VERSION 5.7 ;
BUSBITCHARS "[]" ;
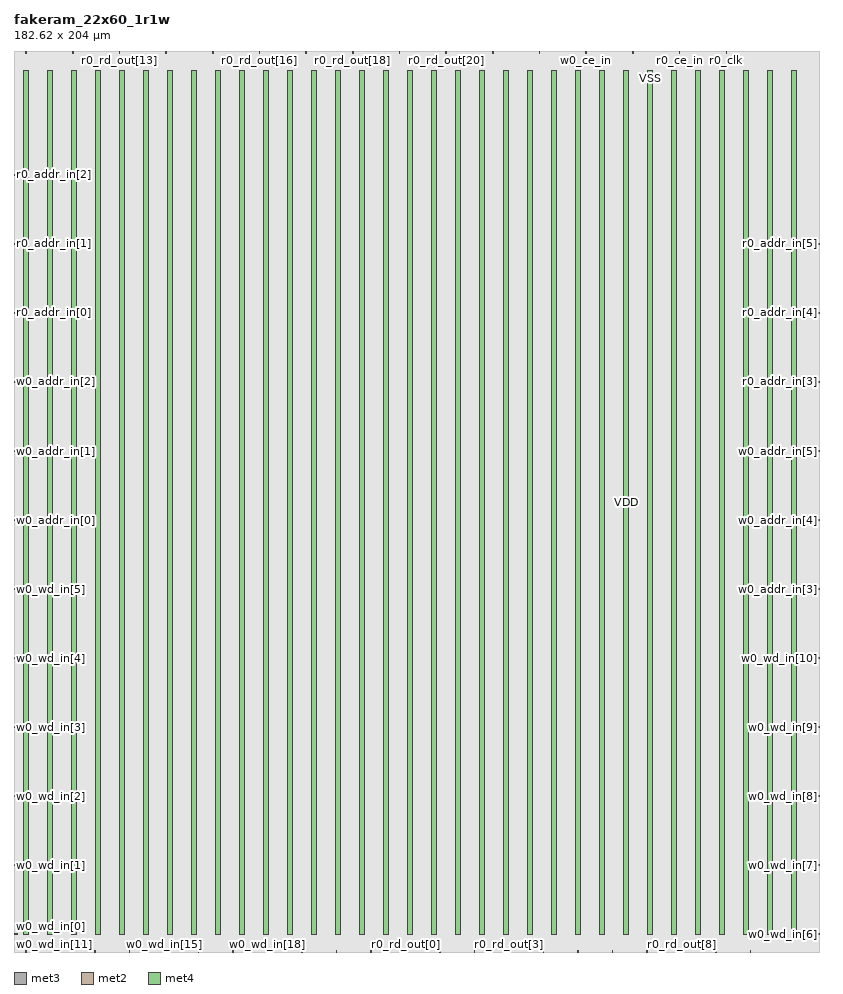
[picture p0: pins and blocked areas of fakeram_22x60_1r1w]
MACRO fakeram_22x60_1r1w
  FOREIGN fakeram_22x60_1r1w 0 0 ;
  SYMMETRY X Y R90 ;
  SIZE 182.620 BY 204.000 ;
  CLASS BLOCK ;
  PIN w0_wd_in[0]
    DIRECTION INPUT ;
    USE SIGNAL ;
    SHAPE ABUTMENT ;
    PORT
      LAYER met3 ;
      RECT 0.000 3.930 0.900 4.230 ;
    END
  END w0_wd_in[0]
  PIN w0_wd_in[1]
    DIRECTION INPUT ;
    USE SIGNAL ;
    SHAPE ABUTMENT ;
    PORT
      LAYER met3 ;
      RECT 0.000 19.570 0.900 19.870 ;
    END
  END w0_wd_in[1]
  PIN w0_wd_in[2]
    DIRECTION INPUT ;
    USE SIGNAL ;
    SHAPE ABUTMENT ;
    PORT
      LAYER met3 ;
      RECT 0.000 35.210 0.900 35.510 ;
    END
  END w0_wd_in[2]
  PIN w0_wd_in[3]
    DIRECTION INPUT ;
    USE SIGNAL ;
    SHAPE ABUTMENT ;
    PORT
      LAYER met3 ;
      RECT 0.000 50.850 0.900 51.150 ;
    END
  END w0_wd_in[3]
  PIN w0_wd_in[4]
    DIRECTION INPUT ;
    USE SIGNAL ;
    SHAPE ABUTMENT ;
    PORT
      LAYER met3 ;
      RECT 0.000 66.490 0.900 66.790 ;
    END
  END w0_wd_in[4]
  PIN w0_wd_in[5]
    DIRECTION INPUT ;
    USE SIGNAL ;
    SHAPE ABUTMENT ;
    PORT
      LAYER met3 ;
      RECT 0.000 82.130 0.900 82.430 ;
    END
  END w0_wd_in[5]
  PIN w0_wd_in[6]
    DIRECTION INPUT ;
    USE SIGNAL ;
    SHAPE ABUTMENT ;
    PORT
      LAYER met3 ;
      RECT 181.720 3.930 182.620 4.230 ;
    END
  END w0_wd_in[6]
  PIN w0_wd_in[7]
    DIRECTION INPUT ;
    USE SIGNAL ;
    SHAPE ABUTMENT ;
    PORT
      LAYER met3 ;
      RECT 181.720 19.570 182.620 19.870 ;
    END
  END w0_wd_in[7]
  PIN w0_wd_in[8]
    DIRECTION INPUT ;
    USE SIGNAL ;
    SHAPE ABUTMENT ;
    PORT
      LAYER met3 ;
      RECT 181.720 35.210 182.620 35.510 ;
    END
  END w0_wd_in[8]
  PIN w0_wd_in[9]
    DIRECTION INPUT ;
    USE SIGNAL ;
    SHAPE ABUTMENT ;
    PORT
      LAYER met3 ;
      RECT 181.720 50.850 182.620 51.150 ;
    END
  END w0_wd_in[9]
  PIN w0_wd_in[10]
    DIRECTION INPUT ;
    USE SIGNAL ;
    SHAPE ABUTMENT ;
    PORT
      LAYER met3 ;
      RECT 181.720 66.490 182.620 66.790 ;
    END
  END w0_wd_in[10]
  PIN w0_wd_in[11]
    DIRECTION INPUT ;
    USE SIGNAL ;
    SHAPE ABUTMENT ;
    PORT
      LAYER met2 ;
      RECT 2.690 0.000 2.830 0.420 ;
    END
  END w0_wd_in[11]
  PIN w0_wd_in[12]
    DIRECTION INPUT ;
    USE SIGNAL ;
    SHAPE ABUTMENT ;
    PORT
      LAYER met2 ;
      RECT 10.510 0.000 10.650 0.420 ;
    END
  END w0_wd_in[12]
  PIN w0_wd_in[13]
    DIRECTION INPUT ;
    USE SIGNAL ;
    SHAPE ABUTMENT ;
    PORT
      LAYER met2 ;
      RECT 18.330 0.000 18.470 0.420 ;
    END
  END w0_wd_in[13]
  PIN w0_wd_in[14]
    DIRECTION INPUT ;
    USE SIGNAL ;
    SHAPE ABUTMENT ;
    PORT
      LAYER met2 ;
      RECT 26.150 0.000 26.290 0.420 ;
    END
  END w0_wd_in[14]
  PIN w0_wd_in[15]
    DIRECTION INPUT ;
    USE SIGNAL ;
    SHAPE ABUTMENT ;
    PORT
      LAYER met2 ;
      RECT 33.970 0.000 34.110 0.420 ;
    END
  END w0_wd_in[15]
  PIN w0_wd_in[16]
    DIRECTION INPUT ;
    USE SIGNAL ;
    SHAPE ABUTMENT ;
    PORT
      LAYER met2 ;
      RECT 41.790 0.000 41.930 0.420 ;
    END
  END w0_wd_in[16]
  PIN w0_wd_in[17]
    DIRECTION INPUT ;
    USE SIGNAL ;
    SHAPE ABUTMENT ;
    PORT
      LAYER met2 ;
      RECT 49.610 0.000 49.750 0.420 ;
    END
  END w0_wd_in[17]
  PIN w0_wd_in[18]
    DIRECTION INPUT ;
    USE SIGNAL ;
    SHAPE ABUTMENT ;
    PORT
      LAYER met2 ;
      RECT 57.430 0.000 57.570 0.420 ;
    END
  END w0_wd_in[18]
  PIN w0_wd_in[19]
    DIRECTION INPUT ;
    USE SIGNAL ;
    SHAPE ABUTMENT ;
    PORT
      LAYER met2 ;
      RECT 65.250 0.000 65.390 0.420 ;
    END
  END w0_wd_in[19]
  PIN w0_wd_in[20]
    DIRECTION INPUT ;
    USE SIGNAL ;
    SHAPE ABUTMENT ;
    PORT
      LAYER met2 ;
      RECT 73.070 0.000 73.210 0.420 ;
    END
  END w0_wd_in[20]
  PIN w0_wd_in[21]
    DIRECTION INPUT ;
    USE SIGNAL ;
    SHAPE ABUTMENT ;
    PORT
      LAYER met2 ;
      RECT 80.890 0.000 81.030 0.420 ;
    END
  END w0_wd_in[21]
  PIN r0_rd_out[0]
    DIRECTION OUTPUT ;
    USE SIGNAL ;
    SHAPE ABUTMENT ;
    PORT
      LAYER met2 ;
      RECT 88.710 0.000 88.850 0.420 ;
    END
  END r0_rd_out[0]
  PIN r0_rd_out[1]
    DIRECTION OUTPUT ;
    USE SIGNAL ;
    SHAPE ABUTMENT ;
    PORT
      LAYER met2 ;
      RECT 96.530 0.000 96.670 0.420 ;
    END
  END r0_rd_out[1]
  PIN r0_rd_out[2]
    DIRECTION OUTPUT ;
    USE SIGNAL ;
    SHAPE ABUTMENT ;
    PORT
      LAYER met2 ;
      RECT 104.350 0.000 104.490 0.420 ;
    END
  END r0_rd_out[2]
  PIN r0_rd_out[3]
    DIRECTION OUTPUT ;
    USE SIGNAL ;
    SHAPE ABUTMENT ;
    PORT
      LAYER met2 ;
      RECT 112.170 0.000 112.310 0.420 ;
    END
  END r0_rd_out[3]
  PIN r0_rd_out[4]
    DIRECTION OUTPUT ;
    USE SIGNAL ;
    SHAPE ABUTMENT ;
    PORT
      LAYER met2 ;
      RECT 119.990 0.000 120.130 0.420 ;
    END
  END r0_rd_out[4]
  PIN r0_rd_out[5]
    DIRECTION OUTPUT ;
    USE SIGNAL ;
    SHAPE ABUTMENT ;
    PORT
      LAYER met2 ;
      RECT 127.810 0.000 127.950 0.420 ;
    END
  END r0_rd_out[5]
  PIN r0_rd_out[6]
    DIRECTION OUTPUT ;
    USE SIGNAL ;
    SHAPE ABUTMENT ;
    PORT
      LAYER met2 ;
      RECT 135.630 0.000 135.770 0.420 ;
    END
  END r0_rd_out[6]
  PIN r0_rd_out[7]
    DIRECTION OUTPUT ;
    USE SIGNAL ;
    SHAPE ABUTMENT ;
    PORT
      LAYER met2 ;
      RECT 143.450 0.000 143.590 0.420 ;
    END
  END r0_rd_out[7]
  PIN r0_rd_out[8]
    DIRECTION OUTPUT ;
    USE SIGNAL ;
    SHAPE ABUTMENT ;
    PORT
      LAYER met2 ;
      RECT 151.270 0.000 151.410 0.420 ;
    END
  END r0_rd_out[8]
  PIN r0_rd_out[9]
    DIRECTION OUTPUT ;
    USE SIGNAL ;
    SHAPE ABUTMENT ;
    PORT
      LAYER met2 ;
      RECT 159.090 0.000 159.230 0.420 ;
    END
  END r0_rd_out[9]
  PIN r0_rd_out[10]
    DIRECTION OUTPUT ;
    USE SIGNAL ;
    SHAPE ABUTMENT ;
    PORT
      LAYER met2 ;
      RECT 166.910 0.000 167.050 0.420 ;
    END
  END r0_rd_out[10]
  PIN r0_rd_out[11]
    DIRECTION OUTPUT ;
    USE SIGNAL ;
    SHAPE ABUTMENT ;
    PORT
      LAYER met2 ;
      RECT 2.690 203.580 2.830 204.000 ;
    END
  END r0_rd_out[11]
  PIN r0_rd_out[12]
    DIRECTION OUTPUT ;
    USE SIGNAL ;
    SHAPE ABUTMENT ;
    PORT
      LAYER met2 ;
      RECT 13.270 203.580 13.410 204.000 ;
    END
  END r0_rd_out[12]
  PIN r0_rd_out[13]
    DIRECTION OUTPUT ;
    USE SIGNAL ;
    SHAPE ABUTMENT ;
    PORT
      LAYER met2 ;
      RECT 23.850 203.580 23.990 204.000 ;
    END
  END r0_rd_out[13]
  PIN r0_rd_out[14]
    DIRECTION OUTPUT ;
    USE SIGNAL ;
    SHAPE ABUTMENT ;
    PORT
      LAYER met2 ;
      RECT 34.430 203.580 34.570 204.000 ;
    END
  END r0_rd_out[14]
  PIN r0_rd_out[15]
    DIRECTION OUTPUT ;
    USE SIGNAL ;
    SHAPE ABUTMENT ;
    PORT
      LAYER met2 ;
      RECT 45.010 203.580 45.150 204.000 ;
    END
  END r0_rd_out[15]
  PIN r0_rd_out[16]
    DIRECTION OUTPUT ;
    USE SIGNAL ;
    SHAPE ABUTMENT ;
    PORT
      LAYER met2 ;
      RECT 55.590 203.580 55.730 204.000 ;
    END
  END r0_rd_out[16]
  PIN r0_rd_out[17]
    DIRECTION OUTPUT ;
    USE SIGNAL ;
    SHAPE ABUTMENT ;
    PORT
      LAYER met2 ;
      RECT 66.170 203.580 66.310 204.000 ;
    END
  END r0_rd_out[17]
  PIN r0_rd_out[18]
    DIRECTION OUTPUT ;
    USE SIGNAL ;
    SHAPE ABUTMENT ;
    PORT
      LAYER met2 ;
      RECT 76.750 203.580 76.890 204.000 ;
    END
  END r0_rd_out[18]
  PIN r0_rd_out[19]
    DIRECTION OUTPUT ;
    USE SIGNAL ;
    SHAPE ABUTMENT ;
    PORT
      LAYER met2 ;
      RECT 87.330 203.580 87.470 204.000 ;
    END
  END r0_rd_out[19]
  PIN r0_rd_out[20]
    DIRECTION OUTPUT ;
    USE SIGNAL ;
    SHAPE ABUTMENT ;
    PORT
      LAYER met2 ;
      RECT 97.910 203.580 98.050 204.000 ;
    END
  END r0_rd_out[20]
  PIN r0_rd_out[21]
    DIRECTION OUTPUT ;
    USE SIGNAL ;
    SHAPE ABUTMENT ;
    PORT
      LAYER met2 ;
      RECT 108.490 203.580 108.630 204.000 ;
    END
  END r0_rd_out[21]
  PIN w0_addr_in[0]
    DIRECTION INPUT ;
    USE SIGNAL ;
    SHAPE ABUTMENT ;
    PORT
      LAYER met3 ;
      RECT 0.000 97.770 0.900 98.070 ;
    END
  END w0_addr_in[0]
  PIN w0_addr_in[1]
    DIRECTION INPUT ;
    USE SIGNAL ;
    SHAPE ABUTMENT ;
    PORT
      LAYER met3 ;
      RECT 0.000 113.410 0.900 113.710 ;
    END
  END w0_addr_in[1]
  PIN w0_addr_in[2]
    DIRECTION INPUT ;
    USE SIGNAL ;
    SHAPE ABUTMENT ;
    PORT
      LAYER met3 ;
      RECT 0.000 129.050 0.900 129.350 ;
    END
  END w0_addr_in[2]
  PIN w0_addr_in[3]
    DIRECTION INPUT ;
    USE SIGNAL ;
    SHAPE ABUTMENT ;
    PORT
      LAYER met3 ;
      RECT 181.720 82.130 182.620 82.430 ;
    END
  END w0_addr_in[3]
  PIN w0_addr_in[4]
    DIRECTION INPUT ;
    USE SIGNAL ;
    SHAPE ABUTMENT ;
    PORT
      LAYER met3 ;
      RECT 181.720 97.770 182.620 98.070 ;
    END
  END w0_addr_in[4]
  PIN w0_addr_in[5]
    DIRECTION INPUT ;
    USE SIGNAL ;
    SHAPE ABUTMENT ;
    PORT
      LAYER met3 ;
      RECT 181.720 113.410 182.620 113.710 ;
    END
  END w0_addr_in[5]
  PIN r0_addr_in[0]
    DIRECTION INPUT ;
    USE SIGNAL ;
    SHAPE ABUTMENT ;
    PORT
      LAYER met3 ;
      RECT 0.000 144.690 0.900 144.990 ;
    END
  END r0_addr_in[0]
  PIN r0_addr_in[1]
    DIRECTION INPUT ;
    USE SIGNAL ;
    SHAPE ABUTMENT ;
    PORT
      LAYER met3 ;
      RECT 0.000 160.330 0.900 160.630 ;
    END
  END r0_addr_in[1]
  PIN r0_addr_in[2]
    DIRECTION INPUT ;
    USE SIGNAL ;
    SHAPE ABUTMENT ;
    PORT
      LAYER met3 ;
      RECT 0.000 175.970 0.900 176.270 ;
    END
  END r0_addr_in[2]
  PIN r0_addr_in[3]
    DIRECTION INPUT ;
    USE SIGNAL ;
    SHAPE ABUTMENT ;
    PORT
      LAYER met3 ;
      RECT 181.720 129.050 182.620 129.350 ;
    END
  END r0_addr_in[3]
  PIN r0_addr_in[4]
    DIRECTION INPUT ;
    USE SIGNAL ;
    SHAPE ABUTMENT ;
    PORT
      LAYER met3 ;
      RECT 181.720 144.690 182.620 144.990 ;
    END
  END r0_addr_in[4]
  PIN r0_addr_in[5]
    DIRECTION INPUT ;
    USE SIGNAL ;
    SHAPE ABUTMENT ;
    PORT
      LAYER met3 ;
      RECT 181.720 160.330 182.620 160.630 ;
    END
  END r0_addr_in[5]
  PIN w0_we_in
    DIRECTION INPUT ;
    USE SIGNAL ;
    SHAPE ABUTMENT ;
    PORT
      LAYER met2 ;
      RECT 119.070 203.580 119.210 204.000 ;
    END
  END w0_we_in
  PIN w0_ce_in
    DIRECTION INPUT ;
    USE SIGNAL ;
    SHAPE ABUTMENT ;
    PORT
      LAYER met2 ;
      RECT 129.650 203.580 129.790 204.000 ;
    END
  END w0_ce_in
  PIN w0_clk
    DIRECTION INPUT ;
    USE SIGNAL ;
    SHAPE ABUTMENT ;
    PORT
      LAYER met2 ;
      RECT 140.230 203.580 140.370 204.000 ;
    END
  END w0_clk
  PIN r0_ce_in
    DIRECTION INPUT ;
    USE SIGNAL ;
    SHAPE ABUTMENT ;
    PORT
      LAYER met2 ;
      RECT 150.810 203.580 150.950 204.000 ;
    END
  END r0_ce_in
  PIN r0_clk
    DIRECTION INPUT ;
    USE SIGNAL ;
    SHAPE ABUTMENT ;
    PORT
      LAYER met2 ;
      RECT 161.390 203.580 161.530 204.000 ;
    END
  END r0_clk
  PIN VSS
    DIRECTION INOUT ;
    USE GROUND ;
    PORT
      LAYER met4 ;
      RECT 2.160 4.080 3.360 199.920 ;
      RECT 13.040 4.080 14.240 199.920 ;
      RECT 23.920 4.080 25.120 199.920 ;
      RECT 34.800 4.080 36.000 199.920 ;
      RECT 45.680 4.080 46.880 199.920 ;
      RECT 56.560 4.080 57.760 199.920 ;
      RECT 67.440 4.080 68.640 199.920 ;
      RECT 78.320 4.080 79.520 199.920 ;
      RECT 89.200 4.080 90.400 199.920 ;
      RECT 100.080 4.080 101.280 199.920 ;
      RECT 110.960 4.080 112.160 199.920 ;
      RECT 121.840 4.080 123.040 199.920 ;
      RECT 132.720 4.080 133.920 199.920 ;
      RECT 143.600 4.080 144.800 199.920 ;
      RECT 154.480 4.080 155.680 199.920 ;
      RECT 165.360 4.080 166.560 199.920 ;
      RECT 176.240 4.080 177.440 199.920 ;
    END
  END VSS
  PIN VDD
    DIRECTION INOUT ;
    USE POWER ;
    PORT
      LAYER met4 ;
      RECT 7.600 4.080 8.800 199.920 ;
      RECT 18.480 4.080 19.680 199.920 ;
      RECT 29.360 4.080 30.560 199.920 ;
      RECT 40.240 4.080 41.440 199.920 ;
      RECT 51.120 4.080 52.320 199.920 ;
      RECT 62.000 4.080 63.200 199.920 ;
      RECT 72.880 4.080 74.080 199.920 ;
      RECT 83.760 4.080 84.960 199.920 ;
      RECT 94.640 4.080 95.840 199.920 ;
      RECT 105.520 4.080 106.720 199.920 ;
      RECT 116.400 4.080 117.600 199.920 ;
      RECT 127.280 4.080 128.480 199.920 ;
      RECT 138.160 4.080 139.360 199.920 ;
      RECT 149.040 4.080 150.240 199.920 ;
      RECT 159.920 4.080 161.120 199.920 ;
      RECT 170.800 4.080 172.000 199.920 ;
    END
  END VDD
  OBS
    LAYER met1 ;
    RECT 0 0 182.620 204.000 ;
    LAYER met2 ;
    RECT 0 0 182.620 204.000 ;
    LAYER met3 ;
    RECT 0 0 182.620 204.000 ;
    LAYER met4 ;
    RECT 0 0 182.620 204.000 ;
  END
END fakeram_22x60_1r1w

END LIBRARY
